One B-rep face of a CAD part: STEP entity #349.
In plain terms, the planar face has unit normal (1, 0, 0).
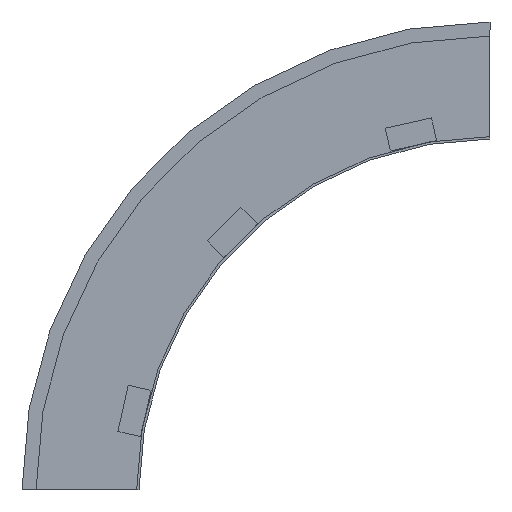
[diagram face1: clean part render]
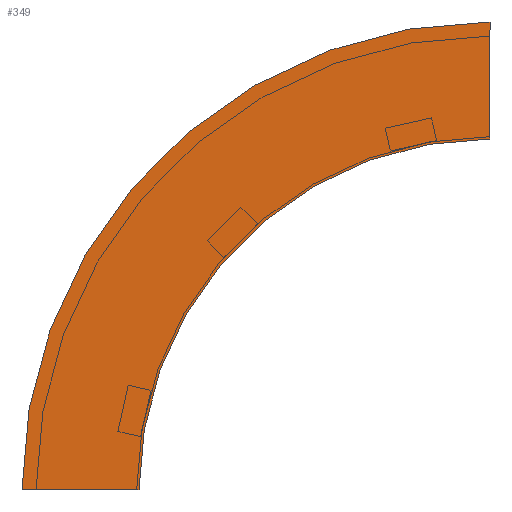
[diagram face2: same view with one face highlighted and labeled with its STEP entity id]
Its self-contained STEP definition (entity closure, numbers rounded to 3 decimals):
#8 = DIRECTION ( 'NONE',  ( 0., 1., 0. ) ) ;
#22 = DIRECTION ( 'NONE',  ( 1., 0., 0. ) ) ;
#24 = EDGE_CURVE ( 'NONE', #97, #142, #481, .T. ) ;
#46 = PLANE ( 'NONE',  #550 ) ;
#63 = CARTESIAN_POINT ( 'NONE',  ( 0., -300., 0. ) ) ;
#83 = DIRECTION ( 'NONE',  ( 0., 1., 0. ) ) ;
#86 = CARTESIAN_POINT ( 'NONE',  ( 0., 0., 0. ) ) ;
#90 = CIRCLE ( 'NONE', #210, 300. ) ;
#97 = VERTEX_POINT ( 'NONE', #311 ) ;
#107 = DIRECTION ( 'NONE',  ( 0., 0., 1. ) ) ;
#125 = ORIENTED_EDGE ( 'NONE', *, *, #24, .T. ) ;
#142 = VERTEX_POINT ( 'NONE', #315 ) ;
#148 = DIRECTION ( 'NONE',  ( 1., 0., 0. ) ) ;
#152 = ORIENTED_EDGE ( 'NONE', *, *, #522, .F. ) ;
#157 = VECTOR ( 'NONE', #107, 1000. ) ;
#176 = DIRECTION ( 'NONE',  ( 0., 0., -1. ) ) ;
#185 = CARTESIAN_POINT ( 'NONE',  ( 0., -300., 400. ) ) ;
#210 = AXIS2_PLACEMENT_3D ( 'NONE', #63, #22, #552 ) ;
#212 = VERTEX_POINT ( 'NONE', #185 ) ;
#221 = DIRECTION ( 'NONE',  ( 1., 0., 0. ) ) ;
#235 = AXIS2_PLACEMENT_3D ( 'NONE', #245, #148, #8 ) ;
#240 = CARTESIAN_POINT ( 'NONE',  ( 0., -300., 300. ) ) ;
#245 = CARTESIAN_POINT ( 'NONE',  ( 0., -300., 0. ) ) ;
#255 = ORIENTED_EDGE ( 'NONE', *, *, #421, .T. ) ;
#266 = FACE_OUTER_BOUND ( 'NONE', #297, .T. ) ;
#297 = EDGE_LOOP ( 'NONE', ( #255, #152, #554, #125 ) ) ;
#311 = CARTESIAN_POINT ( 'NONE',  ( 0., 0., 0. ) ) ;
#315 = CARTESIAN_POINT ( 'NONE',  ( 0., 100., 0. ) ) ;
#340 = VECTOR ( 'NONE', #83, 1000. ) ;
#349 = ADVANCED_FACE ( 'NONE', ( #266 ), #46, .T. ) ;
#411 = CARTESIAN_POINT ( 'NONE',  ( 0., 0., 0. ) ) ;
#421 = EDGE_CURVE ( 'NONE', #142, #212, #578, .T. ) ;
#469 = CARTESIAN_POINT ( 'NONE',  ( 0., -300., 300. ) ) ;
#475 = EDGE_CURVE ( 'NONE', #97, #543, #90, .T. ) ;
#481 = LINE ( 'NONE', #86, #340 ) ;
#522 = EDGE_CURVE ( 'NONE', #543, #212, #563, .T. ) ;
#543 = VERTEX_POINT ( 'NONE', #469 ) ;
#550 = AXIS2_PLACEMENT_3D ( 'NONE', #411, #221, #176 ) ;
#552 = DIRECTION ( 'NONE',  ( 0., 1., 0. ) ) ;
#554 = ORIENTED_EDGE ( 'NONE', *, *, #475, .F. ) ;
#563 = LINE ( 'NONE', #240, #157 ) ;
#578 = CIRCLE ( 'NONE', #235, 400. ) ;
